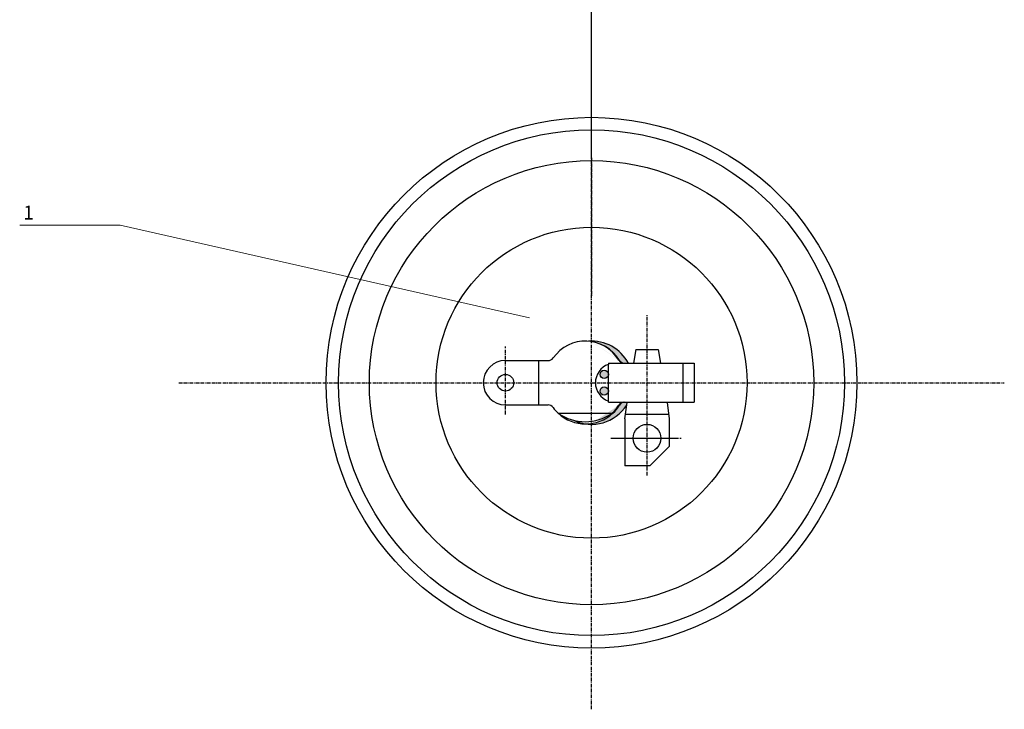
# Model space of a CAD drawing. Units: millimetres. Extents: x -103 to 120, y -59 to 190.
import ezdxf

# ---------------------------------------------------------------- set-up
doc = ezdxf.new("R2010")
doc.units = ezdxf.units.MM
doc.header["$LTSCALE"] = 0.2
doc.linetypes.add('ACAD_ISO10W100', pattern=[18, 12, -3, 0, -3])
pattern_1 = [(45, (0, 0), (-0.561266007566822, 0.5612660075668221), [])]

# ---------------------------------------------------------------- blocks, each defined once
blk = doc.blocks.new('RPG_40_zentr_trubka')
at = {"lineweight": 15, "ltscale": 0.25}
h = blk.add_hatch(dxfattribs=at)
h.set_pattern_fill('ANSI31', scale=0.25, style=0)
h.set_pattern_definition(pattern_1)
edge = h.paths.add_edge_path()
edge.add_line((-4.299999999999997, 84.50779463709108), (-3.799999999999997, 85.00779463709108))
edge.add_line((-5.499999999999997, 84.50779463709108), (-4.299999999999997, 84.50779463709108))
edge.add_line((-5.499999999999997, 84.50779463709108), (-5.999999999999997, 85.00779463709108))
edge.add_line((-5.999999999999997, 85.00779463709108), (-5.999999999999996, 98.50779463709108))
edge.add_line((-3.799999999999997, 85.00779463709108), (-3.799999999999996, 100.5077946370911))
edge.add_line((-6.049999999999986, 178.5077946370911), (-6.050000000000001, 98.50779463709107))
edge.add_line((-3.799999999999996, 100.5077946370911), (-4.989999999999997, 100.5077946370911))
edge.add_line((-6.050000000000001, 98.50779463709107), (-5.999999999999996, 98.50779463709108))
edge.add_line((-4.999999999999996, 100.5176469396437), (-4.999999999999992, 178.0077946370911))
edge.add_line((-6.049999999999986, 178.5077946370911), (-5.499999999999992, 178.5077946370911))
edge.add_line((-4.999999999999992, 178.0077946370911), (-5.499999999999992, 178.5077946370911))
h = blk.add_hatch(dxfattribs=at)
h.set_pattern_fill('ANSI31', scale=0.25, style=0)
h.set_pattern_definition(pattern_1)
edge = h.paths.add_edge_path()
edge.add_line((4.299999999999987, 84.50779463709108), (3.799999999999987, 85.00779463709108))
edge.add_line((3.799999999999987, 85.00779463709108), (3.799999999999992, 100.5077946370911))
edge.add_line((4.299999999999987, 84.50779463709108), (5.499999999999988, 84.50779463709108))
edge.add_line((5.499999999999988, 84.50779463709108), (5.999999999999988, 85.00779463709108))
edge.add_line((5.999999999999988, 85.00779463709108), (5.999999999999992, 98.50779463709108))
edge.add_line((6.049999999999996, 98.50779463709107), (5.999999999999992, 98.50779463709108))
edge.add_line((6.050000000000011, 178.5077946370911), (6.049999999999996, 98.50779463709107))
edge.add_line((3.799999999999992, 100.5077946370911), (4.989999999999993, 100.5077946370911))
edge.add_line((4.999999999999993, 100.5176469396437), (5.000000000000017, 178.0077946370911))
edge.add_line((5.000000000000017, 178.0077946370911), (5.500000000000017, 178.5077946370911))
edge.add_line((6.050000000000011, 178.5077946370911), (5.500000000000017, 178.5077946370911))
at = {"color": 1, "linetype": 'ACAD_ISO10W100', "lineweight": 25, "ltscale": 0.25}
for p, q in [((7.105427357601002e-15, 114.8260053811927), (1.4210854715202e-14, 189.1520107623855)), ((1.224606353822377e-16, 40.5), (4.673465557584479e-15, 114.8260053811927))]:
    blk.add_line(p, q, dxfattribs=at)
at = {"color": 7, "lineweight": 30, "ltscale": 0.25}
for p, q in [((-6.049999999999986, 178.5077946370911), (-6.050000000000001, 98.50779463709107)), ((-6.049999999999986, 178.5077946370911), (-5.499999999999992, 178.5077946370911)), ((-4.999999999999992, 178.0077946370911), (-5.499999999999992, 178.5077946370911)), ((-5.499999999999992, 178.5077946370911), (5.500000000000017, 178.5077946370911)), ((-4.999999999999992, 178.0077946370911), (1.314548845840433e-14, 178.0077946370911)), ((-4.999999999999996, 100.5176469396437), (-4.999999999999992, 178.0077946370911)), ((5.000000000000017, 178.0077946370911), (1.118203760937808e-14, 178.0077946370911)), ((5.000000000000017, 178.0077946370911), (5.500000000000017, 178.5077946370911)), ((4.999999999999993, 100.5176469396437), (5.000000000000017, 178.0077946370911)), ((6.050000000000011, 178.5077946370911), (5.500000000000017, 178.5077946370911)), ((6.050000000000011, 178.5077946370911), (6.049999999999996, 98.50779463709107)), ((-3.799999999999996, 100.5077946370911), (-4.989999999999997, 100.5077946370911)), ((-3.799999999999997, 85.00779463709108), (-3.799999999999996, 100.5077946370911)), ((3.799999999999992, 100.5077946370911), (-3.799999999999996, 100.5077946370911)), ((3.799999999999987, 85.00779463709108), (3.799999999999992, 100.5077946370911)), ((3.799999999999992, 100.5077946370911), (4.989999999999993, 100.5077946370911)), ((-6.050000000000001, 98.50779463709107), (-5.999999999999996, 98.50779463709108)), ((-5.999999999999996, 98.50779463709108), (-5.299999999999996, 98.50779463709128)), ((-5.999999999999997, 85.00779463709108), (-5.999999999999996, 98.50779463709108)), ((5.999999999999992, 98.50779463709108), (5.299999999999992, 98.50779463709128)), ((5.999999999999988, 85.00779463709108), (5.999999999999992, 98.50779463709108)), ((6.049999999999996, 98.50779463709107), (5.999999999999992, 98.50779463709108)), ((-5.499999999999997, 84.50779463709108), (-5.999999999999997, 85.00779463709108)), ((-5.499999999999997, 84.50779463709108), (-4.299999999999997, 84.50779463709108)), ((-4.299999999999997, 84.50779463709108), (-3.799999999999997, 85.00779463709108)), ((-4.299999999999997, 84.50779463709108), (4.299999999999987, 84.50779463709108)), ((-3.799999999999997, 85.00779463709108), (2.847687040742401e-15, 85.00779463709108)), ((3.799999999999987, 85.00779463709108), (-1.268667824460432e-14, 85.00779463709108)), ((4.299999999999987, 84.50779463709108), (3.799999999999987, 85.00779463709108)), ((4.299999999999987, 84.50779463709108), (5.499999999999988, 84.50779463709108)), ((5.499999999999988, 84.50779463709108), (5.999999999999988, 85.00779463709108))]:
    blk.add_line(p, q, dxfattribs=at)
at = {"color": 7, "lineweight": 15, "ltscale": 0.25}
for p, q in [((-5.299999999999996, 98.50779463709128), (-5.299999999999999, 84.50779463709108)), ((5.299999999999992, 98.50779463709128), (5.299999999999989, 84.50779463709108))]:
    blk.add_line(p, q, dxfattribs=at)
at = {"color": 7, "lineweight": 30, "ltscale": 0.25}
for centre, start, end in [((-4.989999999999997, 100.5177946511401), 179.9039583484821, 270), ((4.989999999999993, 100.5177946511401), 270, 0.09604165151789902)]:
    blk.add_arc(centre, 0.01000001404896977, start, end, dxfattribs=at)

msp = doc.modelspace()

# ---------------------------------------------------------------- hatches: boundary and pattern name
at = {"lineweight": 18, "ltscale": 0.25}
h = msp.add_hatch(color=7, dxfattribs=at)
edge = h.paths.add_edge_path()
edge.add_line((-4.959655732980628e-15, 7.5), (-4.964803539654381e-15, 7.415927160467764))
edge.add_ellipse((-1.081674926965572, -2.857264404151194e-15), major_axis=(-9.205651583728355e-16, 7.499999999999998), ratio=0.9659258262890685, start_angle=302.45069273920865, end_angle=351.41300152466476, ccw=False)
edge.add_arc((5.968896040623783, 4.599999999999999), 1.1, 211.5580230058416, 270.0000000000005)
edge.add_line((5.968896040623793, 3.499999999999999), (6.6332495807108, 3.499999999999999))
edge.add_arc((1.332267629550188e-15, 3.552713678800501e-15), 7.499999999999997, 27.8181392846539, 90.00000000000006)
edge = h.paths.add_edge_path()
edge.add_line((6.330409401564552, -4.02192948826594), (6.394073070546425, -3.544451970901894))
edge.add_line((6.394073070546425, -3.544451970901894), (6.401552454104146, -3.500000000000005))
edge.add_line((6.401552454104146, -3.500000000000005), (5.968896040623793, -3.500000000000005))
edge.add_arc((5.968896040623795, -4.600000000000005), 1.1, 90.00000000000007, 148.4419769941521)
edge.add_ellipse((-1.081674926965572, -2.857264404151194e-15), major_axis=(-9.205651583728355e-16, 7.499999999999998), ratio=0.9659258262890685, start_angle=222.8334280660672, end_angle=237.5493072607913, ccw=False)
edge.add_arc((-1.081674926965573, -0.1342332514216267), 7.283528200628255, 278.54057406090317, 312.5490388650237, ccw=False)
edge.add_line((-5.773159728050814e-15, -7.33699400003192), (-5.783441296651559e-15, -7.500000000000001))
edge.add_arc((-2.220446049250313e-15, 1.332267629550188e-15), 7.500000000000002, 270, 327.5707837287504)
at = {"lineweight": 30, "ltscale": 0.25}
h = msp.add_hatch(color=7, dxfattribs=at)
h.paths.add_polyline_path([(1.543826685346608, -1.5, 1), (3.043826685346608, -1.5, 1)])
h.paths.add_polyline_path([(3.043826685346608, 1.5, 1), (1.543826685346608, 1.5, 1)])

# ---------------------------------------------------------------- linework, layer by layer
at = {"color": 1, "linetype": 'ACAD_ISO10W100', "lineweight": 25, "ltscale": 0.25}
for p, q in [((1.224606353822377e-16, 40.5), (4.673465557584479e-15, 114.8260053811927)), ((-1.915390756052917e-15, 15.3057838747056), (2.635614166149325e-15, 89.63178925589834)), ((1.224606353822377e-16, 40.5), (-4.469813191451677e-15, 15.5)), ((-9.020818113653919e-15, -58.82600538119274), (-4.469813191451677e-15, 15.5)), ((10, -16.70910772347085), (10.00000000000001, 12.19518841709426)), ((-15.5, -5.734932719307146), (-15.5, 6.533503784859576)), ((-74.32600538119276, 1.77635683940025e-14), (-5.329070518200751e-15, 0)), ((0, 0), (74.32600538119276, -1.77635683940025e-14)), ((10, -15.73493271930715), (10, -3.466496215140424)), ((3.470334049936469, -9.999999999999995), (15.56286634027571, -9.999999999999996)), ((3.891576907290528, -10), (16.16001341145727, -10.00000000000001))]:
    msp.add_line(p, q, dxfattribs=at)
at = {"color": 7, "lineweight": 15, "ltscale": 0.25}
for p, q in [((-102.9621303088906, 28.39019339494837), (-84.88514227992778, 28.39019339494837)), ((-84.88514227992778, 28.39019339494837), (-11.17745222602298, 11.69250358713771))]:
    msp.add_line(p, q, dxfattribs=at)
at = {"color": 7, "lineweight": 30, "ltscale": 0.25}
for p, q in [((8.000000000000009, 5.999999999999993), (7.579355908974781, 3.499999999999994)), ((8.000000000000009, 5.999999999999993), (12.00000000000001, 5.999999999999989)), ((12.00000000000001, 5.999999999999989), (12.42064409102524, 3.499999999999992)), ((-15.5, 4.000000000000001), (-7.800658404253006, 3.999999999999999)), ((-9.499999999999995, -4), (-9.499999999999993, 3.999999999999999)), ((3.043826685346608, 3.5), (3.043826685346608, 3.302704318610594)), ((3.043826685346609, 3.5), (18.5043546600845, 3.499999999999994)), ((3.043826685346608, -3.302704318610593), (3.043826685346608, 3.302704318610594)), ((16.47876575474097, -3.500000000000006), (16.47876575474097, 3.499999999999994)), ((18.5043546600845, 3.499999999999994), (18.5043546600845, -3.500000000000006)), ((3.043826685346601, -3.500000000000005), (3.043826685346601, -3.302704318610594)), ((3.043826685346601, -3.500000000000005), (18.5043546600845, -3.500000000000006)), ((6.000000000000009, -6.500000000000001), (6.394073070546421, -3.544451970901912)), ((6.401552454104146, -3.500000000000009), (6.394073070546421, -3.544451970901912)), ((13.6059269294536, -3.544451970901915), (6.394073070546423, -3.544451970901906)), ((13.59844754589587, -3.500000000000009), (13.6059269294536, -3.544451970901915)), ((13.6059269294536, -3.544451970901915), (14.00000000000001, -6.500000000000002)), ((-15.50000000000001, -3.999999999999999), (-7.800658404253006, -4.000000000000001)), ((-6.006949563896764, -5.500000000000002), (3.741619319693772, -5.500000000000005)), ((6.000000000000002, -6.500000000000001), (6, -15)), ((6.113858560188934, -5.646060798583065), (13.88614143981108, -5.646060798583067)), ((14, -6.500000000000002), (14, -11.5)), ((14, -11.5), (10.5, -15)), ((10.5, -15), (6, -15))]:
    msp.add_line(p, q, dxfattribs=at)
for centre, radius in [((0, 0), 47.79999999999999), ((0, 0), 45.55), ((0, 0), 40), ((0, 0), 28), ((2.293826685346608, 1.5), 0.75), ((-15.5, 0), 1.5), ((-15.5, 6.847696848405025e-16), 1.5), ((2.293826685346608, -1.5), 0.75), ((10, -9.999999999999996), 2.5)]:
    msp.add_circle(centre, radius, dxfattribs=at)
for centre, radius, start, end in [((0, 0), 7.5, 27.81813928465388, 94.25040445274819), ((-15.5, 6.847696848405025e-16), 4, 90, 270), ((-7.800658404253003, 5.099999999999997), 1.1, 269.9999999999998, 324.4514178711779), ((5.84236637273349, 4.599999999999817), 1.1, 211.0932940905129, 270.0000000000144), ((5.968896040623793, 4.599999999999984), 1.1, 211.5580230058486, 270.0000000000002), ((4.20233615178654, -4.42761482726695e-16), 3.5, 109.329646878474, 250.6703531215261), ((5.842366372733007, -4.600000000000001), 1.1, 89.99999999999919, 148.9067059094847), ((5.968896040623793, -4.600000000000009), 1.1, 90, 148.4419769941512), ((-7.800658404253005, -5.100000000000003), 1.1, 35.54858212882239, 90), ((0, 0), 7.5, 244.5355562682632, 327.5707837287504), ((-1.081674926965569, -0.1342332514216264), 7.283528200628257, 227.4509611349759, 312.5490388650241), ((-1.132665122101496, 1.486785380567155), 8.519026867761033, 235.0987012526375, 304.9012987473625)]:
    msp.add_arc(centre, radius, start, end, dxfattribs=at)
for major_axis, ratio, start_param, end_param in [((-9.205651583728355e-16, 7.499999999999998), 0.9659258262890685, 5.278760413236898, 7.217053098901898), ((-9.594481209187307e-16, 7.499999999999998), 0.9459258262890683, 5.279965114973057, 6.283185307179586), ((-9.205651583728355e-16, 7.499999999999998), 0.9659258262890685, 2.20772486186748, 2.394008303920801), ((-9.594481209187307e-16, 7.499999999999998), 0.9459258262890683, 10.1723623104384, 10.42799815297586), ((-9.205651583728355e-16, 7.499999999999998), 0.9659258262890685, 3.889177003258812, 4.146017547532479)]:
    msp.add_ellipse((-1.081674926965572, -2.857264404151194e-15), major_axis=major_axis, ratio=ratio, start_param=start_param, end_param=end_param, dxfattribs=at)

# ---------------------------------------------------------------- block references
at = {"color": 7, "lineweight": 18, "ltscale": 0.25}
msp.add_blockref('RPG_40_zentr_trubka', (0, 0.4499999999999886), dxfattribs=at)

# ---------------------------------------------------------------- texts
at = {"color": 7, "lineweight": 15, "ltscale": 0.25}
msp.add_text('1', height=2.5, dxfattribs=at).set_placement((-102.3244688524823, 29.39301316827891))

doc.saveas('drawing.dxf')
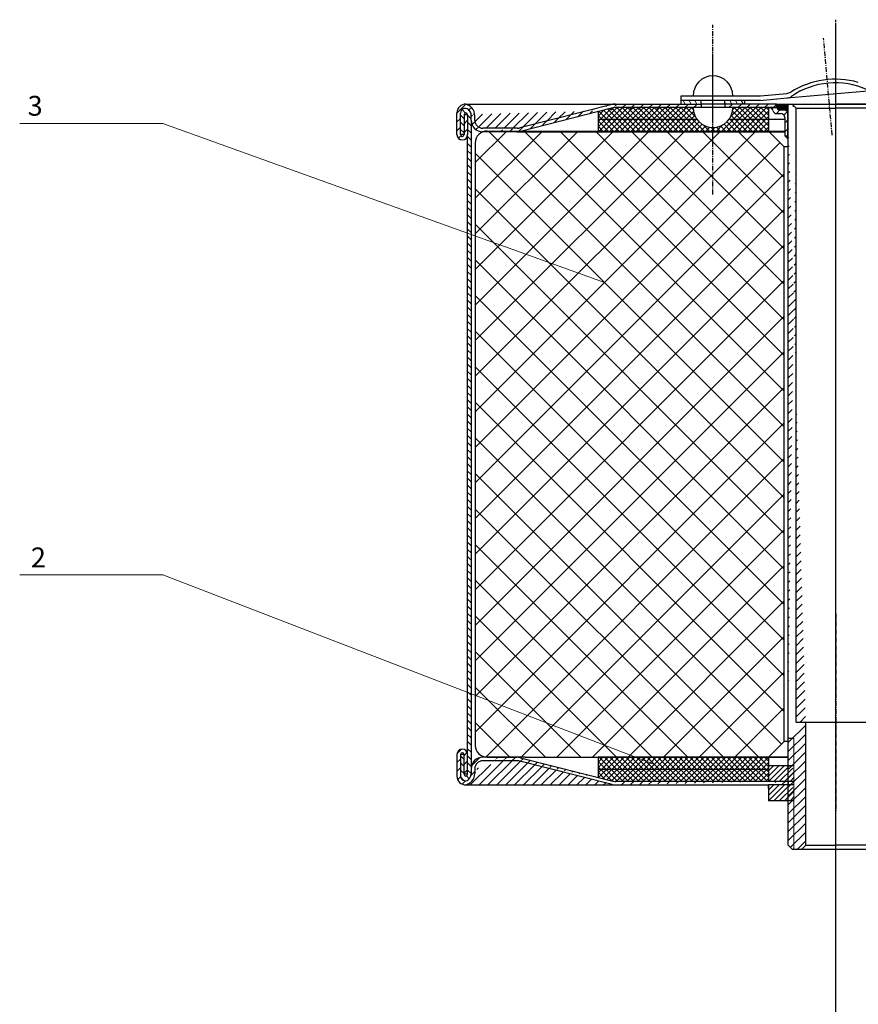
# Model space of a CAD drawing. Units: millimetres. Extents: x -103 to 120, y -59 to 190.
import ezdxf

# ---------------------------------------------------------------- set-up
doc = ezdxf.new("R2010")
doc.units = ezdxf.units.MM
doc.header["$LTSCALE"] = 0.2
doc.linetypes.add('ACAD_ISO10W100', pattern=[18, 12, -3, 0, -3])
pattern_1 = [(45, (0, 0), (-0.561266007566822, 0.5612660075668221), [])]
pattern_2 = [(45, (0, 0), (-0.3367596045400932, 0.3367596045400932), []), (135, (0, 0), (-0.3367596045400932, -0.3367596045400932), [])]

# ---------------------------------------------------------------- blocks, each defined once
blk = doc.blocks.new('RPG_40_zentr_trubka')
at = {"lineweight": 15, "ltscale": 0.25}
h = blk.add_hatch(dxfattribs=at)
h.set_pattern_fill('ANSI31', scale=0.25, style=0)
h.set_pattern_definition(pattern_1)
edge = h.paths.add_edge_path()
edge.add_line((-4.299999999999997, 84.50779463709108), (-3.799999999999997, 85.00779463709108))
edge.add_line((-5.499999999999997, 84.50779463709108), (-4.299999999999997, 84.50779463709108))
edge.add_line((-5.499999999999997, 84.50779463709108), (-5.999999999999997, 85.00779463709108))
edge.add_line((-5.999999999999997, 85.00779463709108), (-5.999999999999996, 98.50779463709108))
edge.add_line((-3.799999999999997, 85.00779463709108), (-3.799999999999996, 100.5077946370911))
edge.add_line((-6.049999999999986, 178.5077946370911), (-6.050000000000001, 98.50779463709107))
edge.add_line((-3.799999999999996, 100.5077946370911), (-4.989999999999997, 100.5077946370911))
edge.add_line((-6.050000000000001, 98.50779463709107), (-5.999999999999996, 98.50779463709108))
edge.add_line((-4.999999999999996, 100.5176469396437), (-4.999999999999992, 178.0077946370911))
edge.add_line((-6.049999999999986, 178.5077946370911), (-5.499999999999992, 178.5077946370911))
edge.add_line((-4.999999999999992, 178.0077946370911), (-5.499999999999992, 178.5077946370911))
at = {"color": 1, "linetype": 'ACAD_ISO10W100', "lineweight": 25, "ltscale": 0.25}
for p, q in [((7.105427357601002e-15, 114.8260053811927), (1.4210854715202e-14, 189.1520107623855)), ((1.224606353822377e-16, 40.5), (4.673465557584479e-15, 114.8260053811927))]:
    blk.add_line(p, q, dxfattribs=at)
at = {"color": 7, "lineweight": 30, "ltscale": 0.25}
for p, q in [((-6.049999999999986, 178.5077946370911), (-6.050000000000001, 98.50779463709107)), ((-6.049999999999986, 178.5077946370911), (-5.499999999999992, 178.5077946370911)), ((-4.999999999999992, 178.0077946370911), (-5.499999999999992, 178.5077946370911)), ((-5.499999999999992, 178.5077946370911), (5.500000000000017, 178.5077946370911)), ((-4.999999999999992, 178.0077946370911), (1.314548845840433e-14, 178.0077946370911)), ((-4.999999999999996, 100.5176469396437), (-4.999999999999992, 178.0077946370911)), ((5.000000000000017, 178.0077946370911), (1.118203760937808e-14, 178.0077946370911)), ((-3.799999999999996, 100.5077946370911), (-4.989999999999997, 100.5077946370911)), ((-3.799999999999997, 85.00779463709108), (-3.799999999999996, 100.5077946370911)), ((3.799999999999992, 100.5077946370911), (-3.799999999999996, 100.5077946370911)), ((-6.050000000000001, 98.50779463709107), (-5.999999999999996, 98.50779463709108)), ((-5.999999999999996, 98.50779463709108), (-5.299999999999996, 98.50779463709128)), ((-5.999999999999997, 85.00779463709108), (-5.999999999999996, 98.50779463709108)), ((-5.499999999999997, 84.50779463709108), (-5.999999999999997, 85.00779463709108)), ((-5.499999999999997, 84.50779463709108), (-4.299999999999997, 84.50779463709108)), ((-4.299999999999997, 84.50779463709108), (-3.799999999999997, 85.00779463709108)), ((-4.299999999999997, 84.50779463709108), (4.299999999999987, 84.50779463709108)), ((-3.799999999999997, 85.00779463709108), (2.847687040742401e-15, 85.00779463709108)), ((3.799999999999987, 85.00779463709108), (-1.268667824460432e-14, 85.00779463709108))]:
    blk.add_line(p, q, dxfattribs=at)
at = {"color": 7, "lineweight": 15, "ltscale": 0.25}
blk.add_line((-5.299999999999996, 98.50779463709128), (-5.299999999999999, 84.50779463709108), dxfattribs=at)
at = {"color": 7, "lineweight": 30, "ltscale": 0.25}
blk.add_arc((-4.989999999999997, 100.5177946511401), 0.01000001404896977, 179.9039583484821, 270, dxfattribs=at)

msp = doc.modelspace()

# ---------------------------------------------------------------- hatches: boundary and pattern name
at = {"lineweight": 15, "ltscale": 0.25}
h = msp.add_hatch(dxfattribs=at)
h.set_pattern_fill('ANSI31', scale=0.25, style=0)
h.set_pattern_definition(pattern_1)
edge = h.paths.add_edge_path()
edge.add_line((-46.45, 177.6077946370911), (-46.9, 177.6077946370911))
edge.add_line((-46.45, 177.6077946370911), (-46.44999999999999, 175.1077946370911))
edge.add_line((-46.9, 177.6077946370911), (-46.9, 175.1077946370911))
edge.add_arc((-47.125, 175.1077946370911), 0.6750000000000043, 180, 360)
edge.add_arc((-47.125, 175.1077946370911), 0.2250000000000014, 180, 360)
edge.add_line((-47.35, 175.1077946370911), (-47.35, 177.6077946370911))
edge.add_line((-47.8, 175.1077946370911), (-47.80000000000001, 177.8327946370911))
edge.add_arc((-46.67500000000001, 177.8327946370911), 1.125, 90, 180)
edge.add_arc((-46.75, 177.8200445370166), 0.6, 51.31781254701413, 180)
edge.add_arc((-46.99999999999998, 177.5077946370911), 1.45, 0, 83.21876594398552)
edge.add_arc((-46.99999999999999, 177.5077946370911), 1, 0, 51.31781254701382)
edge.add_line((-45.99999999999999, 176.9077946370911), (-45.99999999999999, 177.5077946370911))
edge.add_line((-45.5500001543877, 176.9077947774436), (-45.54999999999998, 177.5077946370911))
edge.add_arc((-44.54999999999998, 176.9077946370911), 1.45, 180, 270)
edge.add_arc((-44.5500001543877, 176.9077946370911), 1, 179.9999919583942, 270)
edge.add_line((-40.14481466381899, 175.9077946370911), (-44.5500001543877, 175.9077946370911))
edge.add_line((-40.20998126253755, 175.4577946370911), (-44.54999999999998, 175.4577946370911))
edge.add_arc((-40.14481466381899, 176.9077946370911), 1, 270, 286.4799732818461)
edge.add_arc((-40.20998126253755, 176.9077946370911), 1.45, 269.9999999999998, 286.4799732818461)
edge.add_line((-28.13886552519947, 178.4667135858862), (-39.79864498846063, 175.5173621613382))
edge.add_line((-28.20135501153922, 178.898227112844), (-39.86113447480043, 175.9488756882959))
edge.add_arc((-27.7900187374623, 177.5077946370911), 1.45, 90, 106.4799732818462)
edge.add_arc((-27.85518533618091, 177.5077946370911), 1, 90, 106.4799732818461)
edge.add_line((-16.99999999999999, 178.5077946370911), (-27.85518533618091, 178.5077946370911))
edge.add_line((-27.7900187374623, 178.9577946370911), (-16.99999999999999, 178.9577946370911))
edge.add_line((-16.99999999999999, 178.9577946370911), (-16.99999999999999, 178.5077946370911))
h = msp.add_hatch(dxfattribs=at)
h.set_pattern_fill('ANSI31', scale=0.2, angle=75.00000000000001, style=0)
h.set_pattern_definition([(120, (0, 0), (-0.5499261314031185, -0.3174999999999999), [])])
h.paths.add_polyline_path([(-16.99999999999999, 179.407794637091), (-19.49999999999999, 179.4077946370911), (-19.49999999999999, 178.9577946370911), (-16.99999999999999, 178.9577946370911)])
h.paths.add_polyline_path([(-11.49999999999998, 179.407794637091), (-13.99999999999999, 179.4077946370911), (-13.99999999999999, 178.9577946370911), (-11.49999999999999, 178.9577946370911)])
h = msp.add_hatch(dxfattribs=at)
h.set_pattern_fill('ANSI31', scale=0.25, style=0)
h.set_pattern_definition([(45, (7.105427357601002e-15, 74.13178925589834), (-0.561266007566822, 0.5612660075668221), [])])
edge = h.paths.add_edge_path()
edge.add_line((-13.99999999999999, 178.9577946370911), (-13.99999999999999, 178.5077946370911))
edge.add_line((-8.418245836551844, 178.5077946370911), (-13.99999999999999, 178.5077946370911))
edge.add_arc((-8.418245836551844, 178.0077946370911), 0.5, 14.47751218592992, 90)
edge.add_arc((-7.449999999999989, 178.2577946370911), 0.5, 194.47751218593, 270)
edge.add_line((-7.449999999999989, 177.7577946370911), (-6.94999999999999, 177.7577946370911))
edge.add_arc((-6.94999999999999, 177.2577946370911), 0.5, 0, 90)
edge.add_line((-6.44999999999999, 177.2577946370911), (-6.44999999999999, 174.9577946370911))
edge.add_line((-6.449999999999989, 174.9577946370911), (-6.049999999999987, 174.9577946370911))
edge.add_line((-6.049999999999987, 174.9577946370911), (-6.049999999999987, 177.7077946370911))
edge.add_arc((-6.549999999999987, 177.7077946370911), 0.5, 0, 90.0000000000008)
edge.add_line((-6.499999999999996, 178.2077946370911), (-6.999999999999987, 178.2077946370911))
edge.add_arc((-6.999999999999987, 178.7077946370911), 0.5, 180, 270)
edge.add_line((-7.499999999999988, 178.9577946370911), (-7.499999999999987, 178.7077946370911))
edge.add_line((-7.499999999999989, 178.9577946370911), (-13.99999999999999, 178.9577946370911))
at = {"lineweight": 18, "ltscale": 0.25}
msp.add_hatch(color=7, dxfattribs=at).paths.add_polyline_path([(-6.049999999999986, 178.957794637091), (-7.499999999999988, 178.9577946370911), (-7.499999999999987, 178.7077946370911, 0.4142135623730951), (-6.999999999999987, 178.2077946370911), (-6.549999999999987, 178.2077946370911, -0.4142135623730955), (-6.049999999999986, 177.7077946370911)])
at = {"lineweight": 15, "ltscale": 0.25}
h = msp.add_hatch(dxfattribs=at)
h.set_pattern_fill('ANSI31', scale=0.2, angle=90, style=0)
h.set_pattern_definition([(135, (0, 0), (-0.4490128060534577, -0.4490128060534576), [])])
edge = h.paths.add_edge_path()
edge.add_line((-46.9, 175.1077946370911), (-47.35, 175.1077946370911))
edge.add_line((-47.35, 175.1077946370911), (-47.35, 177.6077946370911))
edge.add_line((-47.35, 177.6077946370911), (-47.35, 177.8200445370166))
edge.add_arc((-46.75, 177.8200445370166), 0.6, 51.31781254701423, 180, ccw=False)
edge.add_arc((-46.99999999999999, 177.5077946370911), 1, 0, 51.31781254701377, ccw=False)
edge.add_line((-45.99999999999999, 177.5077946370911), (-45.99999999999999, 176.9077946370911))
edge.add_line((-45.99999999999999, 176.9077946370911), (-46.00000000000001, 94.40779463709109))
edge.add_arc((-46.93797342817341, 94.48096639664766), 0.9408231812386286, 306.75423924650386, 355.53936257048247, ccw=False)
edge.add_arc((-46.75, 94.19554473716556), 0.6, 180, 308.68218745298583, ccw=False)
edge.add_line((-47.35, 94.19554473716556), (-47.35, 94.40779463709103))
edge.add_line((-47.35, 94.40779463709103), (-47.35, 96.90779463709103))
edge.add_line((-47.35, 96.90779463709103), (-46.9, 96.90779463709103))
edge.add_line((-46.9, 96.90779463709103), (-46.9, 94.40779463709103))
edge.add_arc((-46.675, 94.40779463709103), 0.2250000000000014, 180, 360)
edge.add_line((-46.45, 94.4077946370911), (-46.44999999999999, 175.1077946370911))
edge.add_line((-46.44999999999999, 175.1077946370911), (-46.45, 177.6077946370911))
edge.add_arc((-46.675, 177.6077946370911), 0.2250000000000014, 0, 180)
edge.add_line((-46.9, 177.6077946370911), (-46.9, 175.1077946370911))
h = msp.add_hatch(dxfattribs=at)
h.set_pattern_fill('ANSI37', scale=0.15, style=0)
h.set_pattern_definition(pattern_2)
h.paths.add_polyline_path([(-17.99999999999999, 178.5077946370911), (-27.8551853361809, 178.5077946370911, 0.07203164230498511), (-28.13886552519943, 178.4667135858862), (-29.99999999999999, 177.995937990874), (-29.99999999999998, 177.032794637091), (-17.5185081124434, 177.032794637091, -0.1590867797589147)])
h.paths.add_polyline_path([(-17.51850811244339, 177.032794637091), (-29.99999999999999, 177.032794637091), (-29.99999999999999, 176.6477946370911), (-29.99999999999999, 175.5577946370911), (-15.49999999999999, 175.5577946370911), (-15.49999999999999, 176.0077946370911, -0.239354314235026)])
h.paths.add_polyline_path([(-8.499999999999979, 176.6477946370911), (-8.499999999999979, 177.032794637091), (-13.48149188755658, 177.032794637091, -0.2393543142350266), (-15.49999999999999, 176.0077946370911), (-15.49999999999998, 175.557794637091), (-8.49999999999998, 175.557794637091)])
h.paths.add_polyline_path([(-8.49999999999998, 178.5077946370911), (-12.99999999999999, 178.5077946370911, -0.1590867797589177), (-13.48149188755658, 177.032794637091), (-8.49999999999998, 177.032794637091)])
h = msp.add_hatch(dxfattribs=at)
h.set_pattern_fill('ANSI37', style=0)
h.set_pattern_definition([(45, (6.217248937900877e-15, -2.950000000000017), (-2.245064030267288, 2.245064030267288), []), (135, (6.217248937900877e-15, -2.950000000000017), (-2.245064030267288, -2.245064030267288), [])])
h.paths.add_polyline_path([(-6.49999999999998, 173.557794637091), (-8.499999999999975, 175.5577946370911), (-43.99999999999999, 175.557794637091, 0.4142135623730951), (-45.49999999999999, 174.057794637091), (-45.49999999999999, 98.05779463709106, 0.4142135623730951), (-43.99999999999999, 96.55779463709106), (-8.499999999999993, 96.55779463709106), (-6.499999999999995, 98.55779463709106)])
h.paths.add_polyline_path([(45.50000000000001, 174.0577946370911, 0.4142135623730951), (44.00000000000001, 175.5577946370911), (8.50000000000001, 175.557794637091), (6.50000000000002, 173.5577946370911), (6.500000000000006, 98.55779463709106), (8.500000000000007, 96.55779463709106), (44.00000000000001, 96.55779463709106, 0.4142135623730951), (45.50000000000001, 98.05779463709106)])
msp.add_hatch(color=7, dxfattribs=at).paths.add_polyline_path([(-6.049999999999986, 174.9577946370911), (-6.449999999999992, 174.957794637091), (-6.049999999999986, 174.5577946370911)])
at = {"lineweight": 18, "ltscale": 0.25}
h = msp.add_hatch(dxfattribs=at)
h.set_pattern_fill('ANSI31', scale=0.25, style=0)
h.set_pattern_definition(pattern_1)
edge = h.paths.add_edge_path()
edge.add_line((-46.45, 94.40779463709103), (-46.9, 94.40779463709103))
edge.add_line((-46.9, 94.40779463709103), (-46.9, 96.90779463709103))
edge.add_line((-46.45, 94.40779463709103), (-46.44999999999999, 96.90779463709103))
edge.add_arc((-47.125, 96.90779463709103), 0.6750000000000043, 0, 180)
edge.add_arc((-47.125, 96.90779463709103), 0.2250000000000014, 0, 180)
edge.add_line((-47.8, 96.90779463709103), (-47.80000000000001, 94.18279463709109))
edge.add_line((-47.35, 96.90779463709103), (-47.35, 94.40779463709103))
edge.add_line((-47.35, 94.40779463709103), (-47.35, 94.19554473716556))
edge.add_arc((-46.67500000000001, 94.18279463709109), 1.125, 180, 270)
edge.add_arc((-46.75, 94.19554473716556), 0.6, 180, 308.6821874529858)
edge.add_arc((-46.99999999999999, 94.5077946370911), 1.45, 276.7812340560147, 360)
edge.add_arc((-46.93797342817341, 94.48096639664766), 0.9408231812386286, 306.7542392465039, 355.5393625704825)
edge.add_line((-45.99999999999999, 95.10779463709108), (-45.99999999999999, 94.5077946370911))
edge.add_line((-45.5500001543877, 95.10779449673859), (-45.55000000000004, 94.50779501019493))
edge.add_arc((-44.55, 95.10779463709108), 1.45, 90, 180)
edge.add_arc((-44.55000015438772, 95.10779463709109), 1, 90, 180.0000080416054)
edge.add_line((-40.20998126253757, 96.55779463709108), (-44.55, 96.55779463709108))
edge.add_line((-40.14481466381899, 96.1077946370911), (-44.55000015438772, 96.10779463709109))
edge.add_arc((-40.20998126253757, 95.10779463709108), 1.45, 73.52002671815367, 90)
edge.add_arc((-40.14481466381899, 95.1077946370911), 1, 73.52002671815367, 90)
edge.add_line((-39.79864498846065, 96.49822711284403), (-28.13886552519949, 93.54887568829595))
edge.add_line((-28.20135501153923, 93.11736216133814), (-39.86113447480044, 96.06671358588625))
edge.add_arc((-27.85518533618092, 94.5077946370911), 1, 253.5200267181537, 270)
edge.add_arc((-27.79001873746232, 94.5077946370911), 1.45, 253.5200267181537, 270)
edge.add_line((-8.500000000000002, 93.50779463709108), (-27.85518533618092, 93.5077946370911))
edge.add_line((-27.79001873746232, 93.05779463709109), (-8.498909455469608, 93.05779463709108))
edge.add_line((-6, 93.50779463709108), (-8.500000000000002, 93.50779463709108))
edge.add_line((-6, 93.05779463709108), (-8.5, 93.05779463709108))
edge.add_line((-6, 93.50779463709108), (-6, 93.05779463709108))
at = {"lineweight": 15, "ltscale": 0.25}
h = msp.add_hatch(dxfattribs=at)
h.set_pattern_fill('ANSI37', scale=0.15, style=0)
h.set_pattern_definition(pattern_2)
h.paths.add_polyline_path([(-8.49999999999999, 96.55779463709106), (-29.99999999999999, 96.55779463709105), (-30, 95.05779463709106), (-8.49999999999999, 95.05779463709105)])
h.paths.add_polyline_path([(-8.500000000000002, 95.05779463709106), (-30, 95.05779463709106), (-30, 94.69779463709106), (-29.99999999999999, 94.01965128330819), (-28.13886552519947, 93.54887568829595, 0.07203164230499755), (-27.85518533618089, 93.5077946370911), (-8.500000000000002, 93.50779463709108)])
at = {"lineweight": 18, "ltscale": 0.25}
h = msp.add_hatch(dxfattribs=at)
h.set_pattern_fill('ANSI31', scale=0.15, style=0)
h.set_pattern_definition([(45, (-24.32600538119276, 50.71937272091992), (-0.3367596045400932, 0.3367596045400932), [])])
h.paths.add_polyline_path([(-6, 95.50779463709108), (-8.500000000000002, 95.50779463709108), (-8.500000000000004, 93.50779463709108), (-6, 93.50779463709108)])
h.paths.add_polyline_path([(-5.25, 95.00779463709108), (-5.749999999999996, 95.50779463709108), (-6, 95.50779463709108), (-6, 93.50779463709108), (-5.750000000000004, 93.50779463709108), (-5.25, 94.00779463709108)])
h.paths.add_polyline_path([(6, 95.50779463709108), (5.749999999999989, 95.50779463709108), (5.25, 95.00779463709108), (5.25, 94.00779463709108), (5.750000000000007, 93.50779463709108), (6.000000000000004, 93.50779463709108)])
h.paths.add_polyline_path([(8.500000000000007, 95.50779463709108), (6.000000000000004, 95.50779463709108), (6, 93.50779463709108), (8.500000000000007, 93.50779463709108)])
h = msp.add_hatch(dxfattribs=at)
h.set_pattern_fill('ANSI31', scale=0.15, style=0)
h.set_pattern_definition([(45, (-24.32600538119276, 48.26937272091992), (-0.3367596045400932, 0.3367596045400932), [])])
h.paths.add_polyline_path([(-5.999999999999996, 93.05779463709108), (-8.499999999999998, 93.05779463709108), (-8.5, 91.05779463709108), (-5.999999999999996, 91.05779463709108)])
h.paths.add_polyline_path([(-5.249999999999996, 92.55779463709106), (-5.749999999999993, 93.05779463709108), (-5.999999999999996, 93.05779463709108), (-5.999999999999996, 91.05779463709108), (-5.75, 91.05779463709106), (-5.249999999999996, 91.55779463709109)])
h.paths.add_polyline_path([(6.000000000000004, 93.05779463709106), (5.749999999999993, 93.05779463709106), (5.250000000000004, 92.55779463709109), (5.250000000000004, 91.55779463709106), (5.750000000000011, 91.05779463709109), (6.000000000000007, 91.05779463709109)])
h.paths.add_polyline_path([(8.50000000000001, 93.05779463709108), (6.000000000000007, 93.05779463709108), (6.000000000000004, 91.05779463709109), (8.50000000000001, 91.05779463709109)])

# ---------------------------------------------------------------- linework, layer by layer
at = {"color": 1, "linetype": 'ACAD_ISO10W100', "lineweight": 25, "ltscale": 0.25}
for p, q in [((-15.49999999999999, 167.5693532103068), (-15.49999999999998, 188.9577946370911)), ((7.105427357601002e-15, 114.8260053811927), (1.4210854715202e-14, 189.1520107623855)), ((7.22788799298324e-15, 114.6317892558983), (1.177889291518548e-14, 188.9577946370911)), ((-0.4675447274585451, 175.0501939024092), (-1.549606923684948, 187.2708189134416)), ((-15.49999999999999, 173.6728619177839), (-15.49999999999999, 185.9412984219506)), ((1.224606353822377e-16, 40.5), (4.673465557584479e-15, 114.8260053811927)), ((7.22788799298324e-15, 114.6317892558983), (2.635614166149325e-15, 89.63178925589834)), ((-1.915390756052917e-15, 15.3057838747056), (2.635614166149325e-15, 89.63178925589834))]:
    msp.add_line(p, q, dxfattribs=at)
at = {"color": 7, "lineweight": 30, "ltscale": 0.25}
for p, q in [((-9.499999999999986, 180.0077946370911), (-6.169718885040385, 180.3026708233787)), ((-6.143258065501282, 179.7231908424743), (4.50297781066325, 180.665850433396)), ((-46.67500000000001, 178.9577946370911), (-27.7900187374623, 178.9577946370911)), ((-28.20135501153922, 178.898227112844), (-39.86113447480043, 175.9488756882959)), ((-27.7900187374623, 178.9577946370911), (-16.99999999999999, 178.9577946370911)), ((-19.49999999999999, 179.4077946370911), (-19.49999999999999, 180.0077946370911)), ((-19.49999999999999, 180.0077946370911), (-9.499999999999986, 180.0077946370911)), ((-19.49999999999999, 178.9577946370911), (-19.49999999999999, 179.4077946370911)), ((-11.49999999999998, 179.4077946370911), (-19.49999999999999, 179.4077946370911)), ((-9.499999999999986, 179.4077946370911), (-19.49999999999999, 179.4077946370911)), ((-16.99999999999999, 178.9577946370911), (-16.99999999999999, 179.4077946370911)), ((-16.99999999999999, 178.9577946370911), (-16.99999999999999, 178.5077946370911)), ((-13.99999999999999, 178.9577946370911), (-16.99999999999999, 178.9577946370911)), ((-13.99999999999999, 178.9577946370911), (-13.99999999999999, 179.4077946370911)), ((-13.99999999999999, 178.9577946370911), (-13.99999999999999, 178.5077946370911)), ((-7.499999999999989, 178.9577946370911), (-13.99999999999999, 178.9577946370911)), ((-11.49999999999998, 178.9577946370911), (-11.49999999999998, 179.4077946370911)), ((-9.603570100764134, 179.4168012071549), (-6.143258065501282, 179.7231908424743)), ((-7.499999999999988, 178.9577946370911), (-7.499999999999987, 178.7077946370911)), ((-7.499999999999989, 178.9577946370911), (1.116658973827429e-14, 178.9577946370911)), ((7.500000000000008, 178.9577946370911), (8.717377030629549e-15, 178.9577946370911)), ((-47.8, 175.1077946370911), (-47.80000000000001, 177.8327946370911)), ((-47.35, 177.6077946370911), (-47.35, 177.8200445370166)), ((-28.13886552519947, 178.4667135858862), (-39.79864498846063, 175.5173621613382)), ((-29.99999999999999, 177.995937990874), (-29.99999999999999, 176.6477946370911)), ((-6.037455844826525, 178.5077946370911), (-27.86918887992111, 178.5077946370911)), ((-16.99999999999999, 178.5077946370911), (-27.85518533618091, 178.5077946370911)), ((-13.99999999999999, 178.5077946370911), (-16.99999999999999, 178.5077946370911)), ((-8.418245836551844, 178.5077946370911), (-13.99999999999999, 178.5077946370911)), ((-8.499999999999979, 178.5077946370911), (-8.499999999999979, 176.6477946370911)), ((-8.418245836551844, 178.5077946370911), (-7.458257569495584, 178.5077946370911)), ((-7.449999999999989, 177.7577946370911), (-6.94999999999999, 177.7577946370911)), ((-6.499999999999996, 178.2077946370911), (-6.999999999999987, 178.2077946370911)), ((-6.049999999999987, 174.9577946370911), (-6.049999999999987, 177.7077946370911)), ((-47.35, 175.1077946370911), (-47.35, 177.6077946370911)), ((-46.45, 177.6077946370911), (-46.9, 177.6077946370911)), ((-46.9, 177.6077946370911), (-46.9, 175.1077946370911)), ((-46.45, 177.6077946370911), (-46.44999999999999, 175.1077946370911)), ((-45.99999999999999, 176.9077946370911), (-45.99999999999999, 177.5077946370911)), ((-45.99999999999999, 176.9077946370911), (-46.00000000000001, 94.40779463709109)), ((-45.54999999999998, 177.5077946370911), (-45.54999999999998, 177.5077946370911)), ((-45.5500001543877, 176.9077947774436), (-45.54999999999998, 177.5077946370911)), ((-29.99999999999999, 177.032794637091), (-17.51850811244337, 177.032794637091)), ((-29.99999999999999, 176.6477946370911), (-29.99999999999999, 175.557794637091)), ((-13.48149188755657, 177.032794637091), (-6.449999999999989, 177.032794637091)), ((-8.499999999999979, 176.6477946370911), (-8.499999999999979, 175.5577946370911)), ((-6.44999999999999, 177.2577946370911), (-6.44999999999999, 174.9577946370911)), ((-40.14481466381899, 175.9077946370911), (-44.5500001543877, 175.9077946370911)), ((-40.20998126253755, 175.4577946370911), (-44.54999999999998, 175.4577946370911)), ((-43.99999999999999, 175.557794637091), (-6.44999999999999, 175.557794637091)), ((-40.20998126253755, 175.4577946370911), (-6.44999999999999, 175.4577946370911)), ((-6.49999999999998, 173.5577946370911), (-8.499999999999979, 175.5577946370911)), ((-46.9, 175.1077946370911), (-47.35, 175.1077946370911)), ((-46.45, 94.4077946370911), (-46.44999999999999, 175.1077946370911)), ((-45.49999999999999, 174.057794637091), (-45.49999999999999, 98.05779463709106)), ((-6.449999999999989, 174.9577946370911), (-6.049999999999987, 174.9577946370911)), ((-6.499999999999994, 98.55779463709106), (-6.49999999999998, 173.5577946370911)), ((-6.049999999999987, 173.5577946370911), (-6.49999999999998, 173.5577946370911)), ((-6.499999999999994, 98.55779463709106), (-8.499999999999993, 96.55779463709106)), ((-5.999999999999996, 98.55779463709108), (-6.499999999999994, 98.55779463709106)), ((-47.8, 96.90779463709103), (-47.80000000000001, 94.18279463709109)), ((-46.9, 96.90779463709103), (-47.35, 96.90779463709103)), ((-47.35, 96.90779463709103), (-47.35, 94.40779463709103)), ((-46.9, 94.40779463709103), (-46.9, 96.90779463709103)), ((-46.45, 94.40779463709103), (-46.44999999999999, 96.90779463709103)), ((-40.20998126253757, 96.55779463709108), (-44.55, 96.55779463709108)), ((-40.14481466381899, 96.1077946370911), (-44.55000015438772, 96.10779463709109)), ((-43.99999999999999, 96.55779463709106), (-40.20998126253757, 96.55779463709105)), ((-39.19126765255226, 96.55779463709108), (-40.08932081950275, 96.55779463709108)), ((-28.20135501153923, 93.11736216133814), (-39.86113447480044, 96.06671358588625)), ((-39.79864498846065, 96.49822711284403), (-28.13886552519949, 93.54887568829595)), ((-39.19126765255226, 96.55779463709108), (-6.450000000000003, 96.55779463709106)), ((-38.78374441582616, 96.55779463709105), (-5.999999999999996, 96.55779463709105)), ((-30, 96.55779463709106), (-30, 94.69779463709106)), ((-5.999999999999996, 96.55779463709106), (-30, 96.55779463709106)), ((-8.49999999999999, 96.55779463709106), (-8.49999999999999, 94.69779463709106)), ((-6.450000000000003, 96.55779463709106), (-5.999999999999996, 96.55779463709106)), ((-47.35, 94.40779463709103), (-47.35, 94.19554473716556)), ((-46.45, 94.40779463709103), (-46.9, 94.40779463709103)), ((-45.99999999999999, 95.10779463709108), (-45.99999999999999, 94.5077946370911)), ((-45.5500001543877, 95.10779449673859), (-45.55000000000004, 94.50779501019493)), ((-45.55, 94.5077946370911), (-45.55, 94.5077946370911)), ((-30, 95.05779463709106), (-8.49999999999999, 95.05779463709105)), ((-30, 94.69779463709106), (-30, 94.0196512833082)), ((-8.500000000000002, 95.50779463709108), (-5.299999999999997, 95.50779463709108)), ((-8.500000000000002, 95.05779463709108), (-8.500000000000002, 95.50779463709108)), ((-8.500000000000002, 95.50779463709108), (-8.500000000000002, 93.50779463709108)), ((-8.500000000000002, 93.50779463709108), (-27.85518533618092, 93.5077946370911)), ((-6, 93.50779463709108), (-8.500000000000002, 93.50779463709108)), ((-6, 93.50779463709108), (-6, 93.05779463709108)), ((-5.299999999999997, 93.50779463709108), (-6, 93.50779463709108)), ((-46.68146690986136, 93.05779463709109), (-27.79001873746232, 93.05779463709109)), ((-27.79001873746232, 93.05779463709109), (-8.498909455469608, 93.05779463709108)), ((-8.499999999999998, 93.05779463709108), (-8.498909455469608, 93.05779463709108)), ((-8.499999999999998, 92.60779463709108), (-8.499999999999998, 93.05779463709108)), ((-8.499999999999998, 93.05779463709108), (-8.499999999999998, 91.05779463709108)), ((-6, 93.05779463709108), (-8.5, 93.05779463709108)), ((-5.299999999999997, 93.05779463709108), (-6, 93.05779463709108)), ((-5.299999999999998, 91.05779463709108), (-8.499999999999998, 91.05779463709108))]:
    msp.add_line(p, q, dxfattribs=at)
at = {"color": 7, "lineweight": 15, "ltscale": 0.25}
for p, q in [((-29.99999999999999, 177.995937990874), (-29.99999999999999, 176.6477946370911)), ((-8.499999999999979, 176.6477946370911), (-8.499999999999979, 178.5077946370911)), ((-84.88514227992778, 176.4908321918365), (-102.9621303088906, 176.4908321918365)), ((-84.88514227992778, 176.4908321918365), (-29.18583239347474, 156.4495461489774)), ((-6.049999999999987, 174.5577946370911), (-6.449999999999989, 174.9577946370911)), ((-84.88514227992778, 119.5843475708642), (-102.9621303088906, 119.5843475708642)), ((-22.89965310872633, 95.63972768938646), (-84.88514227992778, 119.5843475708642)), ((-30, 96.55779463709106), (-30, 94.69779463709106)), ((-8.49999999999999, 96.55779463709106), (-30, 96.55779463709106)), ((-8.49999999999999, 94.69779463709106), (-8.49999999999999, 96.55779463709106)), ((-6, 95.05779463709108), (-6, 95.50779463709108)), ((-6, 95.50779463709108), (-6, 93.50779463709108)), ((-8.500000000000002, 93.50779463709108), (-17.78287133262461, 93.50779463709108)), ((-5.999999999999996, 92.60779463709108), (-5.999999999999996, 93.05779463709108)), ((-5.999999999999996, 93.05779463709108), (-5.999999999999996, 91.05779463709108))]:
    msp.add_line(p, q, dxfattribs=at)
at = {"color": 7, "lineweight": 30, "ltscale": 0.25}
for centre, radius, start, end in [((-15.49999999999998, 180.0077946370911), 2.5, 0, 180), ((-0.05479616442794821, 171.5508570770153), 10.54310969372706, 74.25589234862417, 122.2442346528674), ((-0.08347322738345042, 171.8747309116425), 9.758382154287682, 65.57805844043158, 124.5419368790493), ((-6.266737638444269, 181.398383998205), 1.1, 275.0599976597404, 302.2442346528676), ((-46.67500000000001, 177.8327946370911), 1.125, 90, 180), ((-46.99999999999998, 177.5077946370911), 1.45, 0, 83.21876594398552), ((-27.7900187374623, 177.5077946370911), 1.45, 90, 106.4799732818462), ((-6.240276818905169, 180.8189040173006), 1.1, 275.0599976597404, 304.5419368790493), ((-46.75, 177.8200445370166), 0.6, 51.31781254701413, 180), ((-46.675, 177.6077946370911), 0.2250000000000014, 0, 180), ((-46.99999999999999, 177.5077946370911), 1, 0, 51.31781254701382), ((-27.85518533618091, 177.5077946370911), 1, 90, 106.4799732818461), ((-15.49999999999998, 178.5077946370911), 2.5, 180, 0), ((-8.418245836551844, 178.0077946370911), 0.5, 14.47751218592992, 90), ((-7.449999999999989, 178.2577946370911), 0.5, 194.47751218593, 270), ((-6.999999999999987, 178.7077946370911), 0.5, 180, 270), ((-6.94999999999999, 177.2577946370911), 0.5, 0, 90), ((-6.549999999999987, 177.7077946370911), 0.5, 0, 90.0000000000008), ((-44.54999999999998, 176.9077946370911), 1.45, 180, 270), ((-44.5500001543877, 176.9077946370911), 1, 179.9999919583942, 270), ((-43.99999999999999, 174.057794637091), 1.5, 90, 180), ((-40.20998126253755, 176.9077946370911), 1.45, 269.9999999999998, 286.4799732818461), ((-40.14481466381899, 176.9077946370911), 1, 270, 286.4799732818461), ((-47.125, 175.1077946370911), 0.6750000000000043, 180, 0), ((-47.125, 175.1077946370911), 0.2250000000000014, 180, 0), ((-47.125, 96.90779463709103), 0.6750000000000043, 0, 180), ((-47.125, 96.90779463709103), 0.2250000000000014, 0, 180), ((-43.99999999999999, 98.05779463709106), 1.5, 180, 270), ((-44.55, 95.10779463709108), 1.45, 90, 180), ((-44.55000015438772, 95.10779463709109), 1, 90, 180.0000080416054), ((-40.20998126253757, 95.10779463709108), 1.45, 73.52002671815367, 90), ((-40.14481466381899, 95.1077946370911), 1, 73.52002671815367, 90), ((-46.675, 94.40779463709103), 0.2250000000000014, 180, 0), ((-46.99999999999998, 94.50779463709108), 1.45, 276.7812340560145, 0), ((-46.99999999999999, 94.5077946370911), 1.45, 276.7812340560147, 0), ((-46.93797342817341, 94.48096639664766), 0.9408231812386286, 306.7542392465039, 355.5393625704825), ((-46.67500000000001, 94.18279463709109), 1.125, 180, 270), ((-46.75, 94.19554473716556), 0.6, 180, 308.6821874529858), ((-27.85518533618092, 94.5077946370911), 1, 253.5200267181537, 270), ((-27.79001873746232, 94.5077946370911), 1.45, 253.5200267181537, 270)]:
    msp.add_arc(centre, radius, start, end, dxfattribs=at)

# ---------------------------------------------------------------- block references
at = {"color": 7, "lineweight": 18, "ltscale": 0.25}
msp.add_blockref('RPG_40_zentr_trubka', (0, 0.4499999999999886), dxfattribs=at)

# ---------------------------------------------------------------- texts
at = {"color": 7, "lineweight": 15, "ltscale": 0.25}
for s, p in [('3', (-101.9621303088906, 177.4908321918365)), ('2', (-101.5482536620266, 120.5178937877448))]:
    msp.add_text(s, height=2.5, dxfattribs=at).set_placement(p)

doc.saveas('drawing.dxf')
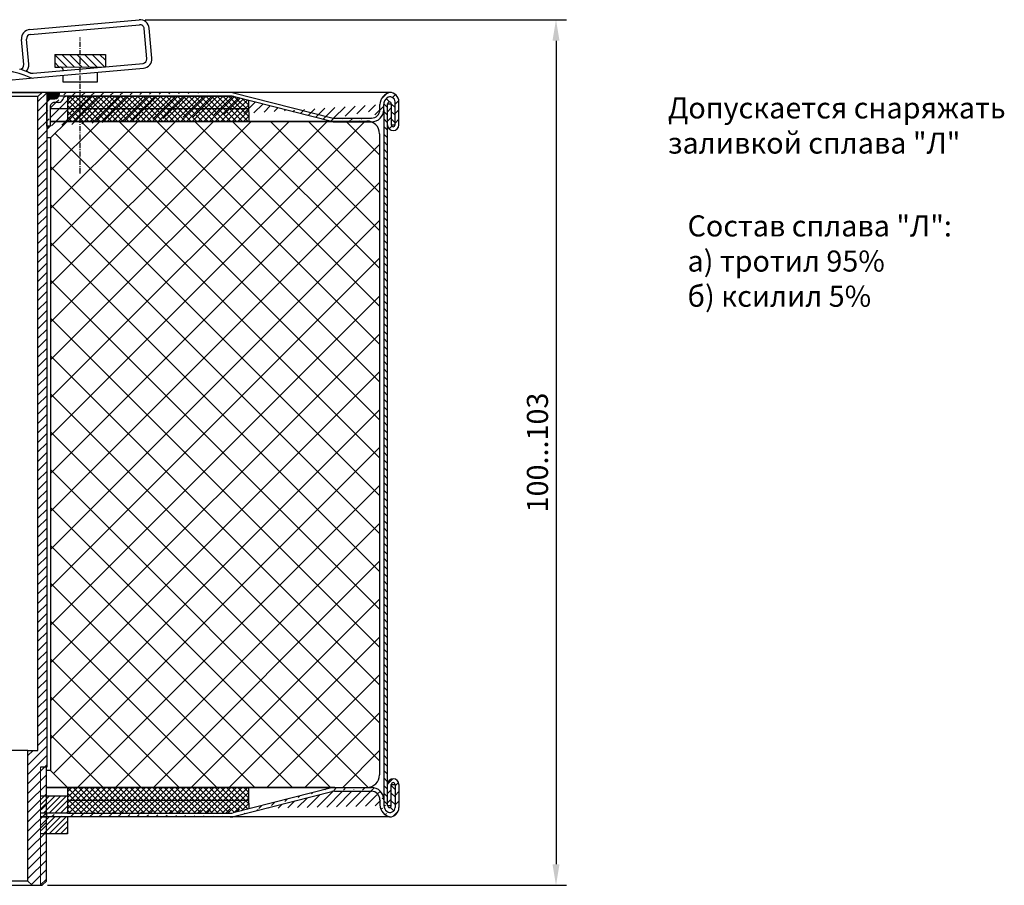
# Model space of a CAD drawing. Units: millimetres. Extents: x -103 to 120, y -59 to 190.
import ezdxf

# ---------------------------------------------------------------- set-up
doc = ezdxf.new("R2010")
doc.units = ezdxf.units.MM
doc.header["$LTSCALE"] = 0.2
doc.linetypes.add('ACAD_ISO02W100', pattern=[15, 12, -3])
doc.linetypes.add('ACAD_ISO10W100', pattern=[18, 12, -3, 0, -3])
doc.dimstyles.new('ISO-25', dxfattribs={"dimtxt": 2.5, "dimasz": 2.5, "dimexe": 1.25, "dimexo": 0.625, "dimtad": 1, "dimtxsty": 'Standard', "dimcen": 2.5, "dimadec": 0, "dimazin": 0, "dimtfac": 1, "dimtmove": 0, "dimatfit": 3, "dimfxl": 0, "dimarcsym": 0})
pattern_1 = [(135, (0, 0), (-0.4490128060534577, -0.4490128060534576), [])]
pattern_2 = [(45, (0, 0), (-0.561266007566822, 0.5612660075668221), [])]
pattern_3 = [(45, (0, 0), (-0.3367596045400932, 0.3367596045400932), []), (135, (0, 0), (-0.3367596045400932, -0.3367596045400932), [])]

# ---------------------------------------------------------------- blocks, each defined once
blk = doc.blocks.new('RPG_40_zentr_trubka')
at = {"lineweight": 15, "ltscale": 0.25}
h = blk.add_hatch(dxfattribs=at)
h.set_pattern_fill('ANSI31', scale=0.25, style=0)
h.set_pattern_definition(pattern_2)
edge = h.paths.add_edge_path()
edge.add_line((4.299999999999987, 84.50779463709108), (3.799999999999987, 85.00779463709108))
edge.add_line((3.799999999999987, 85.00779463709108), (3.799999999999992, 100.5077946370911))
edge.add_line((4.299999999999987, 84.50779463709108), (5.499999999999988, 84.50779463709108))
edge.add_line((5.499999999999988, 84.50779463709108), (5.999999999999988, 85.00779463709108))
edge.add_line((5.999999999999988, 85.00779463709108), (5.999999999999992, 98.50779463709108))
edge.add_line((6.049999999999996, 98.50779463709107), (5.999999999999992, 98.50779463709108))
edge.add_line((6.050000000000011, 178.5077946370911), (6.049999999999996, 98.50779463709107))
edge.add_line((3.799999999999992, 100.5077946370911), (4.989999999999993, 100.5077946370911))
edge.add_line((4.999999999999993, 100.5176469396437), (5.000000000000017, 178.0077946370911))
edge.add_line((5.000000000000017, 178.0077946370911), (5.500000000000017, 178.5077946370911))
edge.add_line((6.050000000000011, 178.5077946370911), (5.500000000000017, 178.5077946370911))
at = {"color": 7, "lineweight": 30, "ltscale": 0.25}
for p, q in [((-5.499999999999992, 178.5077946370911), (5.500000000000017, 178.5077946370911)), ((5.000000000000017, 178.0077946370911), (1.118203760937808e-14, 178.0077946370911)), ((5.000000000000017, 178.0077946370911), (5.500000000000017, 178.5077946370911)), ((4.999999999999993, 100.5176469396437), (5.000000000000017, 178.0077946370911)), ((6.050000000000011, 178.5077946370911), (5.500000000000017, 178.5077946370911)), ((6.050000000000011, 178.5077946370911), (6.049999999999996, 98.50779463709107)), ((3.799999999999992, 100.5077946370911), (-3.799999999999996, 100.5077946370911)), ((3.799999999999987, 85.00779463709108), (3.799999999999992, 100.5077946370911)), ((3.799999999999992, 100.5077946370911), (4.989999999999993, 100.5077946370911)), ((5.999999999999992, 98.50779463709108), (5.299999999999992, 98.50779463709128)), ((5.999999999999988, 85.00779463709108), (5.999999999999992, 98.50779463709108)), ((6.049999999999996, 98.50779463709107), (5.999999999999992, 98.50779463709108)), ((-4.299999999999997, 84.50779463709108), (4.299999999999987, 84.50779463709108)), ((3.799999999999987, 85.00779463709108), (-1.268667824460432e-14, 85.00779463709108)), ((4.299999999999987, 84.50779463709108), (3.799999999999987, 85.00779463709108)), ((4.299999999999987, 84.50779463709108), (5.499999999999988, 84.50779463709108)), ((5.499999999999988, 84.50779463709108), (5.999999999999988, 85.00779463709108))]:
    blk.add_line(p, q, dxfattribs=at)
at = {"color": 7, "lineweight": 15, "ltscale": 0.25}
blk.add_line((5.299999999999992, 98.50779463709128), (5.299999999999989, 84.50779463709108), dxfattribs=at)
at = {"color": 7, "lineweight": 30, "ltscale": 0.25}
blk.add_arc((4.989999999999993, 100.5177946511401), 0.01000001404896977, 270, 0.09604165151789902, dxfattribs=at)
blk = doc.blocks.new('*D10')
at = {"color": 0, "lineweight": -2, "ltscale": 0.25}
for p, q in [((17.71816420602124, 187.5758185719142), (67.67574945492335, 187.5758185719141)), ((66.42574945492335, 185.0758185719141), (66.42574945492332, 87.45779463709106)), ((6.124999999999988, 84.95779463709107), (67.67574945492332, 84.95779463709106))]:
    blk.add_line(p, q, dxfattribs=at)
at = {"color": 0, "lineweight": 15, "ltscale": 0.25}
for points in [[(66.00908278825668, 185.0758185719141), (66.84241612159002, 185.0758185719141), (66.42574945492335, 187.5758185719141)], [(66.00908278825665, 87.45779463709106), (66.84241612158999, 87.45779463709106), (66.42574945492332, 84.95779463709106)]]:
    blk.add_solid(points, dxfattribs=at)
at = {"layer": 'Defpoints', "color": 0, "lineweight": 15, "ltscale": 0.25}
for p in [(17.09316420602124, 187.5758185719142), (5.499999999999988, 84.95779463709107), (66.42574945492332, 84.95779463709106)]:
    blk.add_point(p, dxfattribs=at)
at = {"color": 0, "lineweight": 15, "ltscale": 0.25, "insert": (64.55074945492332, 136.2668066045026), "char_height": 2.5, "attachment_point": 5, "rotation": 90}
blk.add_mtext('100...103', dxfattribs=at)

msp = doc.modelspace()

# ---------------------------------------------------------------- hatches: boundary and pattern name
at = {"lineweight": 15, "ltscale": 0.25}
h = msp.add_hatch(dxfattribs=at)
h.set_pattern_fill('ANSI31', scale=0.2, angle=90, style=0)
h.set_pattern_definition(pattern_1)
h.paths.add_polyline_path([(10.00000000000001, 183.457794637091), (6.990454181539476, 183.457794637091), (6.990454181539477, 181.9577946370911), (7.597136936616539, 181.9621371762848), (10.00000000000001, 181.9793364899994)])
h.paths.add_polyline_path([(13.00954581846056, 183.4577946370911), (10.00000000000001, 183.457794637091), (10.00000000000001, 181.9793364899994), (13.00954581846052, 182.0008783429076)])
at = {"lineweight": 18, "ltscale": 0.25}
h = msp.add_hatch(dxfattribs=at)
h.set_pattern_fill('ANSI31', scale=0.25, style=0)
h.set_pattern_definition(pattern_2)
edge = h.paths.add_edge_path()
edge.add_line((46.45000000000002, 177.6077946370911), (46.90000000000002, 177.6077946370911))
edge.add_line((46.45000000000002, 175.1077946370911), (46.45000000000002, 177.6077946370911))
edge.add_line((46.90000000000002, 177.6077946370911), (46.90000000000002, 175.1077946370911))
edge.add_arc((47.12500000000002, 175.1077946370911), 0.2250000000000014, 180, 360)
edge.add_arc((47.12500000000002, 175.1077946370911), 0.6750000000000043, 180, 360)
edge.add_line((47.80000000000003, 175.1077946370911), (47.80000000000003, 177.832794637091))
edge.add_line((47.35000000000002, 175.1077946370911), (47.35000000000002, 177.6077946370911))
edge.add_line((47.35000000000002, 177.6077946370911), (47.35000000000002, 177.8200445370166))
edge.add_arc((46.75000000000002, 177.8200445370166), 0.6, 0, 128.6821874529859)
edge.add_arc((46.67500000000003, 177.832794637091), 1.125, 0, 89.99999999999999)
edge.add_arc((46.99999999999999, 177.5077946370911), 1.45, 96.8458494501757, 180)
edge.add_arc((47.00000000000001, 177.5077946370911), 1, 128.6821874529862, 180)
edge.add_line((46, 176.9077946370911), (46.00000000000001, 177.5077946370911))
edge.add_line((45.55000015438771, 176.9077947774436), (45.55000000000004, 177.5077942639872))
edge.add_arc((44.55, 176.9077946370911), 1.45, 270, 360)
edge.add_arc((44.55000015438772, 176.9077946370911), 1, 270, 360.0000080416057)
edge.add_line((40.14481466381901, 175.9077946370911), (44.55000015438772, 175.9077946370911))
edge.add_line((40.20998126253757, 175.4577946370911), (44.55, 175.4577946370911))
edge.add_arc((40.14481466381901, 176.9077946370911), 1, 253.5200267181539, 270)
edge.add_arc((40.20998126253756, 176.9077946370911), 1.45, 253.5200267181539, 270.0000000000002)
edge.add_line((39.79864498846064, 175.5173621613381), (28.1388655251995, 178.4667135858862))
edge.add_line((28.20135501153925, 178.898227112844), (39.86113447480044, 175.9488756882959))
edge.add_arc((27.79001873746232, 177.5077946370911), 1.45, 73.52002671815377, 89.99999999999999)
edge.add_arc((27.85518533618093, 177.5077946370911), 1, 73.52002671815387, 89.99999999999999)
edge.add_line((8.418245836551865, 178.5077946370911), (27.85518533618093, 178.5077946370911))
edge.add_line((27.79001873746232, 178.9577946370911), (7.500000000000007, 178.9577946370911))
edge.add_arc((8.418245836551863, 178.0077946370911), 0.5, 89.99999999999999, 165.5224878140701)
edge.add_arc((7.450000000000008, 178.2577946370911), 0.5, 270, 345.5224878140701)
edge.add_line((7.500000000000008, 178.9577946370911), (7.500000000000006, 178.7077946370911))
edge.add_arc((7.000000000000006, 178.7077946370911), 0.5, 270, 360)
edge.add_line((6.500000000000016, 178.2077946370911), (7.000000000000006, 178.2077946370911))
edge.add_arc((6.550000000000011, 177.7077946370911), 0.5, 89.99999999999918, 180)
edge.add_line((7.450000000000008, 177.7577946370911), (6.95000000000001, 177.7577946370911))
edge.add_arc((6.95000000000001, 177.2577946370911), 0.5, 89.99999999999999, 180)
edge.add_line((6.45000000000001, 177.2577946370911), (6.450000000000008, 174.9577946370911))
edge.add_line((6.05000000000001, 174.9577946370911), (6.050000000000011, 177.7077946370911))
edge.add_line((6.45000000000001, 174.9577946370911), (6.05000000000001, 174.9577946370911))
msp.add_hatch(color=7, dxfattribs=at).paths.add_polyline_path([(7.500000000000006, 178.7077946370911), (7.500000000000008, 178.9577946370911), (6.050000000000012, 178.9577946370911), (6.050000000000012, 177.7077946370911, -0.4142135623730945), (6.550000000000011, 178.2077946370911), (7.000000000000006, 178.2077946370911, 0.4142135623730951)])
at = {"lineweight": 15, "ltscale": 0.25}
h = msp.add_hatch(dxfattribs=at)
h.set_pattern_fill('ANSI37', scale=0.15, style=0)
h.set_pattern_definition(pattern_3)
h.paths.add_polyline_path([(30.00000000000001, 177.995937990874), (28.13886552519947, 178.4667135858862, 0.07203164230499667), (27.8551853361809, 178.5077946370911), (10.00000000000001, 178.5077946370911), (10.00000000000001, 177.0327946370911), (30.00000000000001, 177.0327946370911)])
h.paths.add_polyline_path([(30.00000000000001, 176.6477946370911), (30.00000000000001, 177.032794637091), (10.00000000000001, 177.0327946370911), (10.00000000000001, 175.557794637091), (30.00000000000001, 175.557794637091)])
h.paths.add_polyline_path([(10.00000000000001, 178.5077946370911), (8.500000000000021, 178.5077946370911), (8.500000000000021, 177.032794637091), (10.00000000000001, 177.032794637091)])
h.paths.add_polyline_path([(10.00000000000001, 177.0327946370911), (8.500000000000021, 177.0327946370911), (8.500000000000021, 176.6477946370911), (8.500000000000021, 175.557794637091), (10.00000000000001, 175.557794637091)])
h = msp.add_hatch(dxfattribs=at)
h.set_pattern_fill('ANSI31', scale=0.2, angle=90, style=0)
h.set_pattern_definition(pattern_1)
edge = h.paths.add_edge_path()
edge.add_line((46.90000000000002, 175.1077946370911), (47.35000000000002, 175.1077946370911))
edge.add_line((46.90000000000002, 177.6077946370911), (46.90000000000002, 175.1077946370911))
edge.add_line((47.35000000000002, 175.1077946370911), (47.35000000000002, 177.6077946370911))
edge.add_arc((46.75000000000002, 177.8200445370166), 0.6, 0, 128.6821874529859)
edge.add_line((47.35000000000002, 177.6077946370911), (47.35000000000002, 177.8200445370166))
edge.add_arc((47.00000000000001, 177.5077946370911), 1, 128.6821874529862, 180)
edge.add_arc((46.67500000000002, 177.6077946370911), 0.2250000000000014, 0, 180)
edge.add_line((46.45000000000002, 175.1077946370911), (46.45000000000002, 177.6077946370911))
edge.add_line((46, 176.9077946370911), (46.00000000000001, 177.5077946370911))
edge.add_line((46, 176.9077946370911), (45.99999999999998, 94.40779463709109))
edge.add_line((46.45, 94.40779463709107), (46.45, 175.1077946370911))
edge.add_arc((46.93797342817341, 94.48096639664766), 0.9408231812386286, 184.4606374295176, 233.2457607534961)
edge.add_arc((46.675, 94.40779463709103), 0.2250000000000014, 180, 360)
edge.add_arc((46.75000000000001, 94.19554473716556), 0.6, 231.3178125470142, 360)
edge.add_line((47.35000000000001, 96.90779463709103), (47.35000000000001, 94.40779463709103))
edge.add_line((46.90000000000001, 94.40779463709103), (46.90000000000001, 96.90779463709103))
edge.add_line((46.90000000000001, 96.90779463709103), (47.35000000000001, 96.90779463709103))
h = msp.add_hatch(dxfattribs=at)
h.set_pattern_fill('ANSI37', style=0)
h.set_pattern_definition([(45, (6.217248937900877e-15, -2.950000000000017), (-2.245064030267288, 2.245064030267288), []), (135, (6.217248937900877e-15, -2.950000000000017), (-2.245064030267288, -2.245064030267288), [])])
h.paths.add_polyline_path([(-6.49999999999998, 173.557794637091), (-8.499999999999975, 175.5577946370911), (-43.99999999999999, 175.557794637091, 0.4142135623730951), (-45.49999999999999, 174.057794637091), (-45.49999999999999, 98.05779463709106, 0.4142135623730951), (-43.99999999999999, 96.55779463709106), (-8.499999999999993, 96.55779463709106), (-6.499999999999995, 98.55779463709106)])
h.paths.add_polyline_path([(45.50000000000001, 174.0577946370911, 0.4142135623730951), (44.00000000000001, 175.5577946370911), (8.50000000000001, 175.557794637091), (6.50000000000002, 173.5577946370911), (6.500000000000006, 98.55779463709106), (8.500000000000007, 96.55779463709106), (44.00000000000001, 96.55779463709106, 0.4142135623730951), (45.50000000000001, 98.05779463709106)])
msp.add_hatch(color=7, dxfattribs=at).paths.add_polyline_path([(6.45000000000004, 174.9577946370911), (6.05000000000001, 174.9577946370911), (6.05000000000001, 174.5577946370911)])
h = msp.add_hatch(dxfattribs=at)
h.set_pattern_fill('ANSI31', scale=0.25, style=0)
h.set_pattern_definition(pattern_2)
edge = h.paths.add_edge_path(flags=16)
edge.add_arc((46.675, 94.40779463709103), 0.2250000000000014, 180, 360)
edge.add_line((46.90000000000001, 94.40779463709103), (46.45, 94.40779463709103))
edge = h.paths.add_edge_path()
edge.add_line((46.90000000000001, 96.90779463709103), (47.35000000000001, 96.90779463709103))
edge.add_line((46.90000000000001, 94.40779463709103), (46.90000000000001, 96.90779463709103))
edge.add_line((47.35000000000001, 96.90779463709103), (47.35000000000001, 94.40779463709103))
edge.add_line((47.35000000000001, 94.40779463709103), (47.35000000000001, 94.19554473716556))
edge.add_arc((46.75000000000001, 94.19554473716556), 0.6, 231.3178125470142, 360)
edge.add_arc((46.93797342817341, 94.48096639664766), 0.9408231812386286, 184.4606374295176, 233.2457607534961)
edge.add_line((45.99999999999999, 95.10779463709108), (45.99999999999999, 94.5077946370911))
edge.add_line((46.45, 94.40779463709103), (46.45, 96.90779463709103))
edge.add_arc((47.12500000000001, 96.90779463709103), 0.6750000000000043, 0, 180)
edge.add_line((47.80000000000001, 96.90779463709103), (47.80000000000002, 94.18279463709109))
edge.add_arc((46.67500000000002, 94.18279463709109), 1.125, 270, 360)
edge.add_arc((46.99999999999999, 94.50779463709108), 1.45, 180, 263.2187659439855)
edge.add_line((45.55000015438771, 95.10779449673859), (45.55000000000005, 94.50779501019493))
edge.add_arc((44.55000015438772, 95.10779463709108), 1, 359.9999919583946, 450)
edge.add_arc((44.55, 95.10779463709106), 1.45, 0, 90)
edge.add_line((40.14481466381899, 96.10779463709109), (44.55000015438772, 96.10779463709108))
edge.add_line((40.20998126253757, 96.55779463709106), (44.00000000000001, 96.55779463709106))
edge.add_line((44.01840469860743, 96.55779463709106), (44.55, 96.55779463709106))
edge.add_arc((40.20998126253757, 95.10779463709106), 1.45, 90, 106.4799732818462)
edge.add_arc((40.14481466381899, 95.10779463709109), 1, 90, 106.4799732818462)
edge.add_line((28.20135501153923, 93.11736216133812), (39.86113447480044, 96.06671358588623))
edge.add_line((39.79864498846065, 96.49822711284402), (28.13886552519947, 93.54887568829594))
edge.add_arc((27.85518533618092, 94.50779463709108), 1, 270, 286.4799732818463)
edge.add_arc((27.79001873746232, 94.50779463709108), 1.45, 270, 286.4799732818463)
edge.add_line((8.5, 93.5077946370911), (27.85518533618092, 93.50779463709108))
edge.add_line((27.79001873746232, 93.05779463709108), (8.500000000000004, 93.05779463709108))
edge.add_line((8.5, 93.50779463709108), (6, 93.50779463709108))
edge.add_line((8.500000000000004, 93.05779463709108), (6.000000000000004, 93.05779463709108))
edge.add_line((6, 93.50779463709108), (6, 93.05779463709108))
h = msp.add_hatch(dxfattribs=at)
h.set_pattern_fill('ANSI37', scale=0.15, style=0)
h.set_pattern_definition(pattern_3)
h.paths.add_polyline_path([(30, 96.55779463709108), (8.50000000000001, 96.55779463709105), (8.50000000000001, 95.05779463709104), (30, 95.05779463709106)])
h.paths.add_polyline_path([(30, 94.69779463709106), (30, 95.05779463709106), (8.50000000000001, 95.05779463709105), (8.50000000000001, 94.69779463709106), (8.500000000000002, 93.5077946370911), (27.85518533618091, 93.50779463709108, 0.0720316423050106), (28.13886552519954, 93.54887568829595), (30.00000000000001, 94.0196512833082)])
at = {"lineweight": 18, "ltscale": 0.25}
h = msp.add_hatch(dxfattribs=at)
h.set_pattern_fill('ANSI31', scale=0.15, style=0)
h.set_pattern_definition([(45, (-24.32600538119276, 50.71937272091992), (-0.3367596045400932, 0.3367596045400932), [])])
h.paths.add_polyline_path([(-6, 95.50779463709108), (-8.500000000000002, 95.50779463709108), (-8.500000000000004, 93.50779463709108), (-6, 93.50779463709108)])
h.paths.add_polyline_path([(-5.25, 95.00779463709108), (-5.749999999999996, 95.50779463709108), (-6, 95.50779463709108), (-6, 93.50779463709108), (-5.750000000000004, 93.50779463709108), (-5.25, 94.00779463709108)])
h.paths.add_polyline_path([(6, 95.50779463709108), (5.749999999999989, 95.50779463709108), (5.25, 95.00779463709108), (5.25, 94.00779463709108), (5.750000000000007, 93.50779463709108), (6.000000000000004, 93.50779463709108)])
h.paths.add_polyline_path([(8.500000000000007, 95.50779463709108), (6.000000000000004, 95.50779463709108), (6, 93.50779463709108), (8.500000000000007, 93.50779463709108)])
h = msp.add_hatch(dxfattribs=at)
h.set_pattern_fill('ANSI31', scale=0.15, style=0)
h.set_pattern_definition([(45, (-24.32600538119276, 48.26937272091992), (-0.3367596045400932, 0.3367596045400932), [])])
h.paths.add_polyline_path([(-5.999999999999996, 93.05779463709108), (-8.499999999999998, 93.05779463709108), (-8.5, 91.05779463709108), (-5.999999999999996, 91.05779463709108)])
h.paths.add_polyline_path([(-5.249999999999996, 92.55779463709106), (-5.749999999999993, 93.05779463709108), (-5.999999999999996, 93.05779463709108), (-5.999999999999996, 91.05779463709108), (-5.75, 91.05779463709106), (-5.249999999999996, 91.55779463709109)])
h.paths.add_polyline_path([(6.000000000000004, 93.05779463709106), (5.749999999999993, 93.05779463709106), (5.250000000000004, 92.55779463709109), (5.250000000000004, 91.55779463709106), (5.750000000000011, 91.05779463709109), (6.000000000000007, 91.05779463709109)])
h.paths.add_polyline_path([(8.50000000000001, 93.05779463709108), (6.000000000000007, 93.05779463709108), (6.000000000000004, 91.05779463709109), (8.50000000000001, 91.05779463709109)])

# ---------------------------------------------------------------- linework, layer by layer
at = {"color": 7, "lineweight": 30, "ltscale": 0.25}
for p, q in [((4.046807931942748, 186.42494647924), (16.99614545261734, 187.5715317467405)), ((4.099727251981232, 185.8272847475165), (17.04906477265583, 186.973870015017)), ((17.90849611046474, 182.9366068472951), (17.5912156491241, 186.5199180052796)), ((18.50435466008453, 183.0098909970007), (18.18887738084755, 186.5728373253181)), ((3.312592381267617, 182.2452355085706), (3.048113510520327, 185.2322145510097)), ((3.910136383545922, 182.2994844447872), (3.645775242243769, 185.2851338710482)), ((6.990454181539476, 183.457794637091), (13.00954581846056, 183.4577946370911)), ((6.990454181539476, 183.457794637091), (6.990454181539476, 181.9577946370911)), ((13.00954581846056, 183.4577946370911), (13.00954581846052, 182.0008783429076)), ((4.423951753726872, 181.2406760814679), (17.45454410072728, 182.3944559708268)), ((4.50297781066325, 180.665850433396), (17.50566023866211, 181.8171590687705)), ((6.990454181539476, 181.9577946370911), (7.597136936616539, 181.9621371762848)), ((7.597136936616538, 181.9621371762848), (13.00954581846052, 182.0008783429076)), ((8.000000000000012, 181.5621474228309), (8.000000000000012, 181.5573134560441)), ((8.000000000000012, 180.1577946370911), (8.000000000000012, 180.9754905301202)), ((12.00000000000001, 181.3296662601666), (12.00000000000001, 180.1577946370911)), ((-6.143258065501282, 179.7231908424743), (4.50297781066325, 180.665850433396)), ((12.00000000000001, 180.1577946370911), (8.000000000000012, 180.1577946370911)), ((7.500000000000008, 178.9577946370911), (8.717377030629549e-15, 178.9577946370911)), ((14.00000000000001, 178.9577946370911), (6.000000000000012, 178.9577946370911)), ((7.500000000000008, 178.9577946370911), (7.500000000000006, 178.7077946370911)), ((27.79001873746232, 178.9577946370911), (7.500000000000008, 178.9577946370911)), ((46.67500000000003, 178.9577946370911), (27.79001873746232, 178.9577946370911)), ((28.20135501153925, 178.898227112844), (39.86113447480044, 175.9488756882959)), ((6.05000000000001, 174.9577946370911), (6.050000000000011, 177.7077946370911)), ((6.500000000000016, 178.2077946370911), (7.000000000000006, 178.2077946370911)), ((7.450000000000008, 177.7577946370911), (6.95000000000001, 177.7577946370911)), ((27.85624759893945, 178.5077946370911), (7.458257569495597, 178.5077946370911)), ((8.418245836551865, 178.5077946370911), (27.85518533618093, 178.5077946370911)), ((8.500000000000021, 178.5077946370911), (8.500000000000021, 176.6477946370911)), ((39.79864498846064, 175.5173621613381), (28.1388655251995, 178.4667135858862)), ((30.00000000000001, 176.6477946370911), (30.00000000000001, 177.995937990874)), ((45.55, 177.5077946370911), (45.54999999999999, 177.5077946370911)), ((45.55000015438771, 176.9077947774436), (45.55000000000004, 177.5077942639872)), ((46, 176.9077946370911), (46.00000000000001, 177.5077946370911)), ((46.45000000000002, 177.6077946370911), (46.90000000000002, 177.6077946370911)), ((46.45000000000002, 175.1077946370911), (46.45000000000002, 177.6077946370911)), ((46.90000000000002, 177.6077946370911), (46.90000000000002, 175.1077946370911)), ((47.35000000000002, 177.6077946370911), (47.35000000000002, 177.8200445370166)), ((47.35000000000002, 175.1077946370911), (47.35000000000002, 177.6077946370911)), ((47.80000000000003, 175.1077946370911), (47.80000000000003, 177.832794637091)), ((6.45000000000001, 177.2577946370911), (6.450000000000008, 174.9577946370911)), ((6.45000000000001, 177.0327946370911), (30.00000000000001, 177.0327946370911)), ((8.500000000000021, 176.6477946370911), (8.500000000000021, 175.5577946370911)), ((30.00000000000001, 176.6477946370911), (30.00000000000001, 175.5577946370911)), ((46, 176.9077946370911), (45.99999999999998, 94.40779463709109)), ((6.450000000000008, 175.557794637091), (44.00000000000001, 175.5577946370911)), ((40.20998126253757, 175.4577946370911), (6.450000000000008, 175.4577946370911)), ((8.500000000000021, 175.5577946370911), (6.50000000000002, 173.5577946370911)), ((40.14481466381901, 175.9077946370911), (44.55000015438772, 175.9077946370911)), ((40.20998126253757, 175.4577946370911), (44.55, 175.4577946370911)), ((6.45000000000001, 174.9577946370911), (6.05000000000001, 174.9577946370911)), ((45.50000000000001, 174.0577946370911), (45.50000000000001, 98.05779463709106)), ((46.45, 94.40779463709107), (46.45, 175.1077946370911)), ((46.90000000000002, 175.1077946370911), (47.35000000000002, 175.1077946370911)), ((6.50000000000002, 173.5577946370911), (6.05000000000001, 173.5577946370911)), ((6.50000000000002, 173.5577946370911), (6.500000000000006, 98.55779463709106)), ((6.500000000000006, 98.55779463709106), (5.999999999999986, 98.55779463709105)), ((8.500000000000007, 96.55779463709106), (6.500000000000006, 98.55779463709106)), ((46.45, 94.40779463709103), (46.45, 96.90779463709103)), ((46.90000000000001, 94.40779463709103), (46.90000000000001, 96.90779463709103)), ((46.90000000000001, 96.90779463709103), (47.35000000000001, 96.90779463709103)), ((47.35000000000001, 96.90779463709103), (47.35000000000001, 94.40779463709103)), ((47.80000000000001, 96.90779463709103), (47.80000000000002, 94.18279463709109)), ((6.450000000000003, 96.55779463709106), (5.999999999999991, 96.55779463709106)), ((5.999999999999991, 96.55779463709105), (40.20998126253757, 96.55779463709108)), ((30, 96.55779463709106), (5.999999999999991, 96.55779463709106)), ((40.20998126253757, 96.55779463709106), (6.450000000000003, 96.55779463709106)), ((8.50000000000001, 96.55779463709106), (8.50000000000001, 94.69779463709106)), ((39.79864498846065, 96.49822711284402), (28.13886552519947, 93.54887568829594)), ((28.20135501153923, 93.11736216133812), (39.86113447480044, 96.06671358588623)), ((30, 94.69779463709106), (30, 96.55779463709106)), ((40.14481466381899, 96.10779463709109), (44.55000015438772, 96.10779463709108)), ((40.20998126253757, 96.55779463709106), (44.00000000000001, 96.55779463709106)), ((44.01840469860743, 96.55779463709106), (44.55, 96.55779463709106)), ((8.5, 95.50779463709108), (5.299999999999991, 95.50779463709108)), ((8.5, 95.50779463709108), (8.5, 95.05779463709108)), ((8.5, 95.50779463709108), (8.5, 93.50779463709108)), ((8.500000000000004, 95.05779463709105), (30, 95.05779463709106)), ((30, 94.69779463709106), (30, 94.01965128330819)), ((45.55000015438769, 95.10779449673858), (45.55000000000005, 94.50779501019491)), ((45.55000015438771, 95.10779449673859), (45.55000000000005, 94.50779501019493)), ((45.99999999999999, 95.10779463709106), (45.99999999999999, 94.50779463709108)), ((45.99999999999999, 95.10779463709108), (45.99999999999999, 94.5077946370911)), ((6, 93.50779463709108), (5.299999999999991, 93.50779463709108)), ((6, 93.50779463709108), (5.299999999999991, 93.50779463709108)), ((6, 93.50779463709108), (6, 93.05779463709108)), ((8.5, 93.50779463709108), (6, 93.50779463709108)), ((8.5, 93.5077946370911), (27.85518533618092, 93.50779463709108)), ((45.55, 94.50779463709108), (45.55, 94.50779463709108)), ((45.55, 94.5077946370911), (45.55, 94.5077946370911)), ((46.45, 94.40779463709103), (46.90000000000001, 94.40779463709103)), ((47.35000000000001, 94.40779463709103), (47.35000000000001, 94.19554473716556)), ((6, 93.05779463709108), (5.299999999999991, 93.05779463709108)), ((5.299999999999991, 93.05779463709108), (6.000000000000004, 93.05779463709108)), ((8.500000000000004, 93.05779463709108), (6.000000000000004, 93.05779463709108)), ((27.79001873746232, 93.05779463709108), (8.500000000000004, 93.05779463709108)), ((8.500000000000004, 93.05779463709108), (8.500000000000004, 92.60779463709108)), ((8.500000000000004, 93.05779463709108), (8.500000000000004, 91.05779463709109)), ((46.67500000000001, 93.05779463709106), (27.79001873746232, 93.05779463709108)), ((8.500000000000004, 91.05779463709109), (5.295361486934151, 91.05779463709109))]:
    msp.add_line(p, q, dxfattribs=at)
at = {"color": 1, "linetype": 'ACAD_ISO10W100', "lineweight": 25, "ltscale": 0.25}
msp.add_line((10.00000000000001, 169.3604644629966), (10.00000000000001, 185.4620360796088), dxfattribs=at)
at = {"color": 7, "linetype": 'ACAD_ISO02W100', "lineweight": 25, "ltscale": 0.25}
msp.add_line((8.000000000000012, 181.9577946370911), (8.000000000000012, 181.9650208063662), dxfattribs=at)
at = {"color": 7, "lineweight": 15, "ltscale": 0.25}
for p, q in [((6.05000000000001, 174.5577946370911), (6.45000000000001, 174.9577946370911)), ((6, 95.05779463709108), (6, 95.50779463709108)), ((6, 95.50779463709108), (6, 93.50779463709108)), ((6.000000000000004, 92.60779463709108), (6.000000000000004, 93.05779463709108)), ((6.000000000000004, 93.05779463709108), (6.000000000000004, 91.05779463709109))]:
    msp.add_line(p, q, dxfattribs=at)
at = {"color": 7, "lineweight": 30, "ltscale": 0.25}
for centre, radius, start, end in [((17.09316420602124, 186.4758185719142), 1.1, 5.059997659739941, 95.05999765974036), ((17.09316420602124, 186.4758185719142), 0.5, 5.059997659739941, 95.05999765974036), ((4.143826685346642, 185.3292333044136), 1.1, 95.05999765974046, 185.0599976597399), ((4.143826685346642, 185.3292333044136), 0.5, 95.05999765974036, 185.0599976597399), ((2.814540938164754, 182.2011360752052), 0.5, 275.0599976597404, 5.059997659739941), ((2.814423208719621, 182.2024656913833), 1.1, 315.9881417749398, 5.059997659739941), ((17.41044466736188, 182.8925074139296), 0.5, 275.0599976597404, 5.059997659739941), ((17.40864148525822, 182.9128722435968), 1.1, 275.0599976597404, 5.059997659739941), ((-0.08347322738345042, 171.8747309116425), 9.758382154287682, 65.57805844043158, 124.5419368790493), ((-2.30053073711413, 165.9715448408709), 16.55591709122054, 67.95294961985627, 71.84305454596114), ((-0.05479616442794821, 171.5508570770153), 10.54310969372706, 66.46414582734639, 69.68519852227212), ((4.326933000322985, 182.3363892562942), 1.1, 247.9529496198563, 275.0599976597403), ((7.600000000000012, 181.5621474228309), 0.4, 0, 90.41010712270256), ((4.405959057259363, 181.7615636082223), 1.1, 245.5780584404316, 275.0599976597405), ((7.000000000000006, 178.7077946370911), 0.5, 270, 0), ((27.79001873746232, 177.5077946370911), 1.45, 73.52002671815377, 89.99999999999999), ((46.99999999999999, 177.5077946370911), 1.45, 96.8458494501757, 180), ((46.67500000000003, 177.832794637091), 1.125, 0, 89.99999999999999), ((6.550000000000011, 177.7077946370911), 0.5, 89.99999999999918, 180), ((6.95000000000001, 177.2577946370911), 0.5, 89.99999999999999, 180), ((7.450000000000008, 178.2577946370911), 0.5, 270, 345.5224878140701), ((8.418245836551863, 178.0077946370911), 0.5, 89.99999999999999, 165.5224878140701), ((27.85518533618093, 177.5077946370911), 1, 73.52002671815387, 89.99999999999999), ((47.00000000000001, 177.5077946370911), 1, 128.6821874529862, 180), ((46.75000000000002, 177.8200445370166), 0.6, 0, 128.6821874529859), ((46.67500000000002, 177.6077946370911), 0.2250000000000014, 0, 180), ((44.55000015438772, 176.9077946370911), 1, 270, 8.041605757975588e-06), ((44.55, 176.9077946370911), 1.45, 270, 0), ((40.20998126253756, 176.9077946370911), 1.45, 253.5200267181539, 270.0000000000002), ((40.14481466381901, 176.9077946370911), 1, 253.5200267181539, 270), ((44.00000000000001, 174.0577946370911), 1.5, 0, 90), ((47.12500000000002, 175.1077946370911), 0.6750000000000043, 180, 0), ((47.12500000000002, 175.1077946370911), 0.2250000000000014, 180, 0), ((44.00000000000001, 98.05779463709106), 1.5, 270, 0), ((47.12500000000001, 96.90779463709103), 0.6750000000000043, 0, 180), ((47.12500000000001, 96.90779463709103), 0.2250000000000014, 0, 180), ((40.20998126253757, 95.10779463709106), 1.45, 90, 106.4799732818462), ((40.14481466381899, 95.10779463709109), 1, 90, 106.4799732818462), ((44.55, 95.10779463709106), 1.45, 0, 90), ((44.55000015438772, 95.10779463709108), 1, 359.9999919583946, 90), ((27.85518533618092, 94.50779463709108), 1, 270, 286.4799732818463), ((46.99999999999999, 94.5077946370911), 1.45, 180, 263.2187659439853), ((46.99999999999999, 94.50779463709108), 1.45, 180, 263.2187659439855), ((46.93797342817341, 94.48096639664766), 0.9408231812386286, 184.4606374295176, 233.2457607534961), ((46.75000000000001, 94.19554473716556), 0.6, 231.3178125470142, 0), ((46.675, 94.40779463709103), 0.2250000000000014, 180, 0), ((46.67500000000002, 94.18279463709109), 1.125, 270, 0), ((27.79001873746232, 94.50779463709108), 1.45, 270, 286.4799732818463)]:
    msp.add_arc(centre, radius, start, end, dxfattribs=at)

# ---------------------------------------------------------------- block references
at = {"color": 7, "lineweight": 18, "ltscale": 0.25}
msp.add_blockref('RPG_40_zentr_trubka', (0, 0.4499999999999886), dxfattribs=at)

# ---------------------------------------------------------------- texts
at = {"color": 7, "lineweight": 15, "ltscale": 0.25}
for s, p in [('Допускается снаряжать ', (79.68976752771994, 175.8693269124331)), ('заливкой сплава "Л"', (79.68976752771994, 171.7026602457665)), ('Состав сплава "Л":', (82.02348246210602, 161.8775235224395)), ('а) тротил 95%', (82.02348246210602, 157.7108568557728)), ('б) ксилил 5%', (82.02348246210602, 153.5441901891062))]:
    msp.add_text(s, height=2.5, dxfattribs=at).set_placement(p)

# ---------------------------------------------------------------- dimensions: what is measured, and where the dimension line sits
dim = msp.add_linear_dim(base=(66.42574945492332, 84.95779463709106), p1=(17.09316420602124, 187.5758185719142), p2=(5.499999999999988, 84.95779463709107), angle=90, text='100...103', dimstyle='ISO-25', dxfattribs=at)
dim.commit()
dim.dimension.update_dxf_attribs({"geometry": '*D10', "text_midpoint": (64.55074945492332, 136.2668066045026)})

doc.saveas('drawing.dxf')
